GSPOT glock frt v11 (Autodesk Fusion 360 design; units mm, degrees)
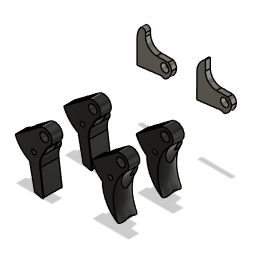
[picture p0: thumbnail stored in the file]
named bodies: "Baseplate - Angled", "Locking Plate", "Magazine", "9mm Follower"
